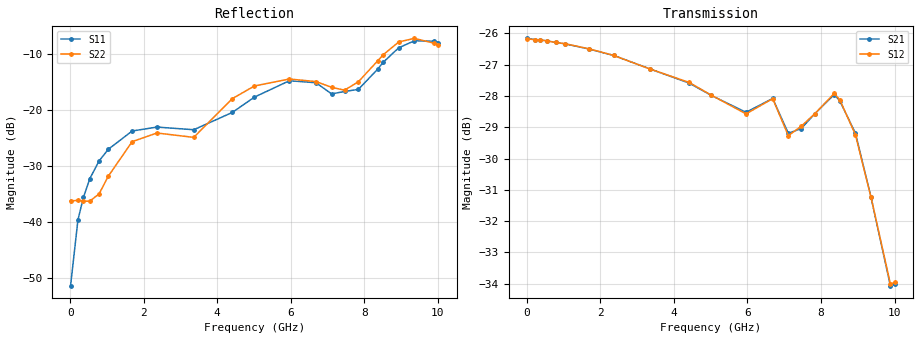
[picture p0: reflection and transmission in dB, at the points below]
! Device ID: PE43704
! Dir: z:\PE43704\PE43704_Char_1_20130516\PE43704\AMB\3p400V\25p25dB
! Serial: 14
! Insertion: A
! Impedance: 50 ohm
! Temp: Amb
! VDD: 3.400V
! Attenuation Step: 25.25dB
! IDD: 1.140853e-01mA
#  Hz  S  RI  R  50
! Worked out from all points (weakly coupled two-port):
!   401 points, 10 MHz to 10.01 GHz, reference 50 ohm
!   highest |S21| = -26.17 dB at 10 MHz (marker M1); lowest = -34.1 dB at 9.885 GHz (marker M2)
!   lowest |S11| = -51.3 dB at 10 MHz (marker M3), VSWR 1.01, Z = 50.3 + j0.0448 ohm
!   |S11| at or under -10 dB: start of sweep to 8.723 GHz
!   |S22| runs from -36.3 to -7.2 dB; largest |S21 - S12| = 0.00082
!   S11 on the Smith chart (normalised r, x): 10 MHz: 1.01, +0.00; 7.46 GHz: 0.78, +0.15; 8.51 GHz: 0.81, +0.46; 9.36 GHz: 0.54, +0.49; 10.01 GHz: 0.47, +0.28
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1e7  0.00268 0.000445  0.0492 -0.000155  0.0491 -0.000143  0.0155 0.000242
2.1e8  0.00141 0.0104  0.0489 -0.00275  0.0489 -0.00269  0.0139 0.00718
3.6e8  -0.00166 0.0166  0.0487 -0.00459  0.0487 -0.00466  0.0105 0.0112
5.35e8  -0.00768 0.0233  0.0483 -0.00668  0.0483 -0.00663  0.00444 0.0148
7.85e8  -0.0195 0.0293  0.0475 -0.0096  0.0475 -0.00962  -0.00731 0.0163
1.035e9  -0.0331 0.03  0.0466 -0.0124  0.0466 -0.0125  -0.0217 0.0138
1.685e9  -0.0631 0.016  0.0432 -0.0193  0.0432 -0.0194  -0.0517 -0.00816
2.36e9  -0.0705 -0.00279  0.0386 -0.0254  0.0386 -0.0254  -0.0572 -0.0251
3.36e9  -0.0668 0.000458  0.03 -0.0321  0.0301 -0.032  -0.057 -0.00329
4.41e9  -0.084 0.0451  0.0213 -0.0359  0.0215 -0.0359  -0.1148 0.0533
5.01e9  -0.1078 0.0736  0.017 -0.0361  0.0171 -0.0361  -0.1501 0.0663
5.96e9  -0.1548 0.097  0.00974 -0.0362  0.01 -0.0359  -0.1726 0.0778
6.685e9  -0.1544 0.0831  0.0059 -0.039  0.00573 -0.039  -0.157 0.0871
7.11e9  -0.1235 0.0645  -0.000437 -0.0347  -0.000334 -0.0344  -0.1172 0.1084
7.46e9  -0.1126 0.0939  0.00046 -0.0353  0.000514 -0.0356  -0.0826 0.1258
7.835e9  -0.0659 0.1379  -0.00104 -0.0373  -0.000881 -0.0373  -0.0602 0.1682
8.36e9  -0.0335 0.2287  -0.0102 -0.0387  -0.0101 -0.0389  -0.0662 0.2663
8.51e9  -0.0363 0.2639  -0.0129 -0.0369  -0.0128 -0.0371  -0.0753 0.3019
8.935e9  -0.0874 0.3488  -0.018 -0.0297  -0.0181 -0.0294  -0.1329 0.3827
9.36e9  -0.1779 0.3749  -0.0165 -0.0219  -0.0165 -0.0219  -0.2081 0.3833
9.885e9  -0.2931 0.2886  -0.00709 -0.0185  -0.00746 -0.0185  -0.2986 0.2594
1.001e10  -0.3125 0.2501  -0.00457 -0.0194  -0.00507 -0.0194  -0.3125 0.2157
